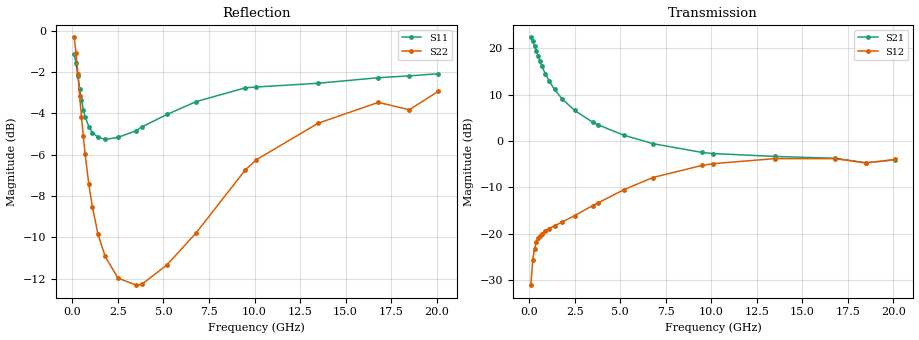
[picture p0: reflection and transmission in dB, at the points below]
!  Infineon Technologies AG
! BFR380L3 , PF131585-7, No.6, Th 09.10.01, soldered on pcb-board, measured with PP GSG850
!  Vce=3.5 V,  Ic=4.0 mA
! Common Emitter S-Parameters:  15. November 2001
#  GHz  S  MA  R  50
! f  S11  S21  S12  S22
! GHz  Mag  Ang  Mag  Ang  Mag  Ang  Mag  Ang
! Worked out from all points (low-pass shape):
!   201 points, 100 MHz to 20.1 GHz, reference 50 ohm
!   highest |S21| = 22.37 dB at 100 MHz (marker M1); lowest = -4.7 dB at 18.5 GHz (marker M2)
!   |S21| within 3 dB of the highest: start of sweep to 398.5 MHz
!   lowest |S11| = -5.3 dB at 1.8 GHz (marker M3), VSWR 3.40, Z = 14.8 - j3 ohm
!   |S11| at or under -10 dB: nowhere
!   |S22| runs from -12.4 to -0.3 dB; largest |S21 - S12| = 13
!   S11 on the Smith chart (normalised r, x): 100 MHz: 1.36, -4.21; 400 MHz: 0.36, -1.08; 1.1 GHz: 0.30, -0.29; 3.8 GHz: 0.29, +0.29; 9.5 GHz: 0.36, +1.09; 20.1 GHz: 0.98, +2.53
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0.1  0.8758 -24.4  13.14 163.5  0.02771 77.4  0.9632 -14.1
0.2  0.8341 -46.8  11.91 148.9  0.05146 65.8  0.8837 -26.5
0.3  0.7783 -66.2  10.57 136.9  0.06876 57.1  0.7871 -36.1
0.4  0.7231 -82.5  9.287 127.1  0.0802 50.9  0.6962 -43.5
0.5  0.6809 -95.8  8.171 119.2  0.08842 46.6  0.6187 -49.1
0.6  0.6437 -107.4  7.225 112.9  0.09487 43.5  0.5551 -53.3
0.7  0.6194 -117.0  6.46 107.4  0.09972 41.4  0.5029 -56.6
0.9  0.5862 -132.5  5.28 98.8  0.1071 39.3  0.4257 -61.5
1.1  0.5665 -144.6  4.454 91.9  0.1132 38.7  0.3744 -65.1
1.4  0.553 -158.4  3.598 83.5  0.1211 39.4  0.3228 -69.3
1.8  0.5457 -172.5  2.869 74.3  0.1326 41.5  0.2844 -74.3
2.5  0.552 169.3  2.137 61.1  0.1561 45.4  0.2522 -84.5
3.5  0.5726 149.7  1.592 45.4  0.2006 49.0  0.2425 -101.4
3.8  0.5848 144.9  1.492 41.6  0.2146 49.4  0.2434 -108.2
5.2  0.6273 124.8  1.153 24.7  0.2973 46.7  0.2716 -135.6
6.8  0.6738 105.6  0.935 10.6  0.4026 39.0  0.3246 -168.2
9.5  0.7274 81.8  0.7516 -4.5  0.5443 20.0  0.4608 149.6
10.1  0.7307 77.5  0.7305 -6.8  0.568 15.6  0.4873 141.3
13.5  0.7462 59.0  0.6803 -20.1  0.6444 -7.8  0.5974 104.9
16.8  0.7695 47.4  0.6496 -31.7  0.6438 -24.9  0.6708 80.1
18.5  0.7773 45.5  0.5797 -39.0  0.5778 -33.6  0.6438 73.7
20.1  0.787 38.4  0.6266 -42.8  0.631 -38.8  0.7139 62.5
